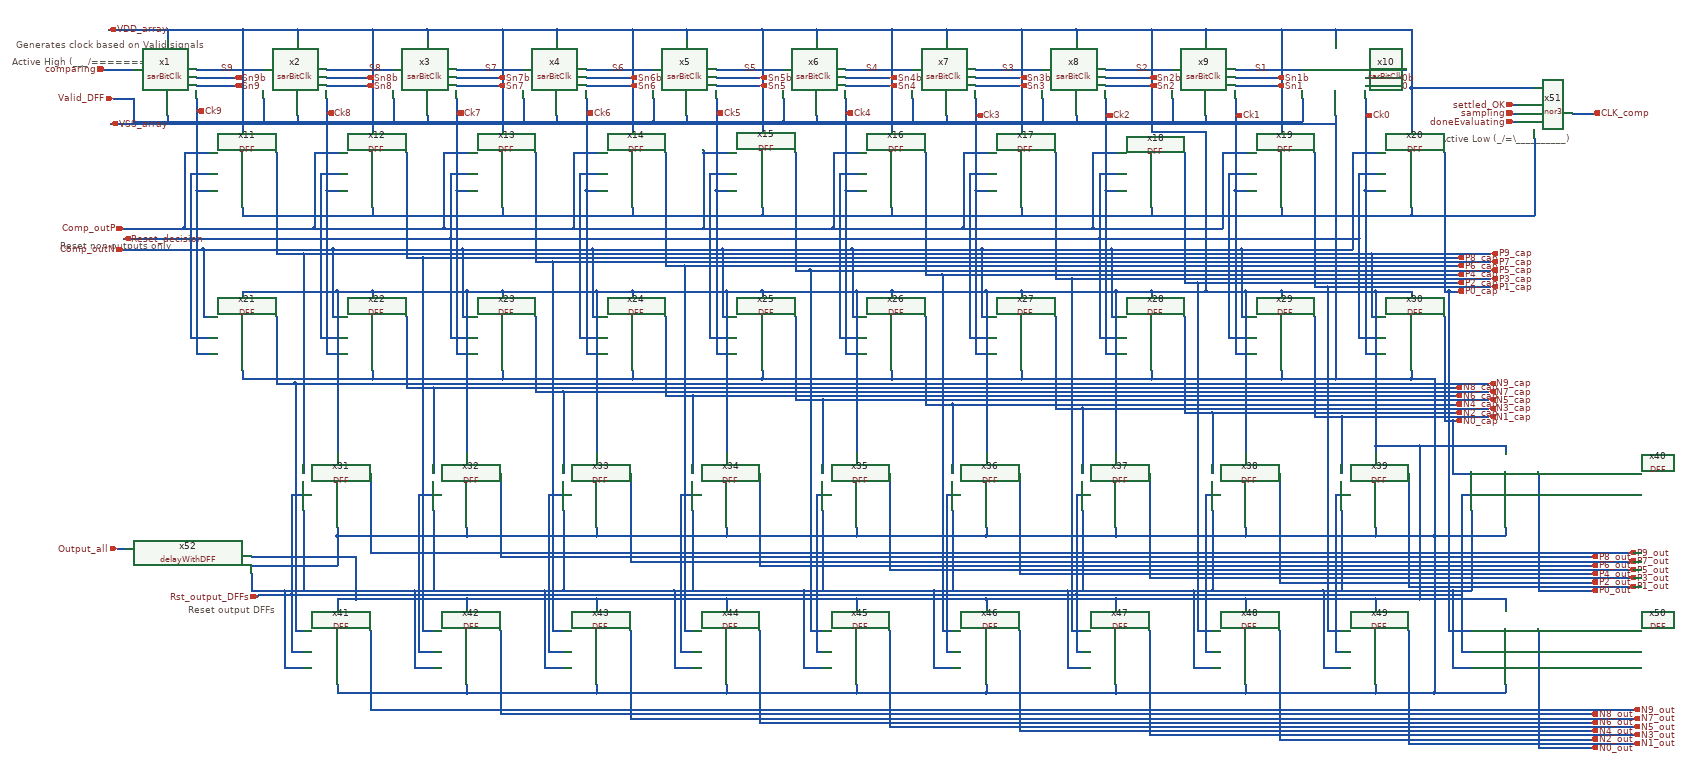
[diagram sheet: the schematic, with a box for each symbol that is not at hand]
v {xschem version=3.4.8RC file_version=1.3}
G {}
K {}
V {}
S {}
F {}
E {}
T {Generates clock based on Valid signals} -520 -755 0 0 0.3 0.3 {}
T {Reset output DFFs} -110 595 0 0 0.3 0.3 {}
T {Active High (___/=========\\_)} -530 -715 0 0 0.3 0.3 {}
T {Active Low (_/=\\__________)} 2880 -530 0 0 0.3 0.3 {}
T {Reset non-outputs only} -415 -275 0 0 0.3 0.3 {}
N -310 -685 -240 -685 {lab=comparing}
N 3195 -580 3245 -580 {lab=CLK_comp}
N 2645 145 2995 145 {lab=N1_cap}
N 2910 155 2915 155 {lab=N0_cap}
N 3115 560 3240 560 {lab=P0_out}
N 2300 -175 2920 -175 {lab=P2_cap}
N 2610 -165 3000 -165 {lab=P1_cap}
N 2900 -155 2920 -155 {lab=P0_cap}
N 2700 -645 2740 -645 {lab=Sn0}
N 2700 -665 2740 -665 {lab=Sn0b}
N -90 -685 70 -685 {lab=S9}
N 220 -685 380 -685 {lab=S8}
N 530 -685 690 -685 {lab=S7}
N 840 -685 1000 -685 {lab=S6}
N 1150 -685 1310 -685 {lab=S5}
N 1460 -685 1620 -685 {lab=S4}
N 1770 -685 1930 -685 {lab=S3}
N 2080 -685 2240 -685 {lab=S2}
N 2390 -685 2550 -685 {lab=S1}
N 2630 -780 2630 -755 {lab=VDD_array}
N 2320 -780 2320 -755 {lab=VDD_array}
N 2190 -780 2320 -780 {lab=VDD_array}
N 2010 -780 2010 -755 {lab=VDD_array}
N 1880 -780 2010 -780 {lab=VDD_array}
N -160 -780 -160 -755 {lab=VDD_array}
N -300 -780 -160 -780 {lab=VDD_array}
N 150 -780 150 -755 {lab=VDD_array}
N 20 -780 150 -780 {lab=VDD_array}
N 460 -780 460 -755 {lab=VDD_array}
N 330 -780 460 -780 {lab=VDD_array}
N 770 -780 770 -755 {lab=VDD_array}
N 640 -780 770 -780 {lab=VDD_array}
N 1390 -780 1390 -755 {lab=VDD_array}
N 1260 -780 1390 -780 {lab=VDD_array}
N 1080 -780 1080 -755 {lab=VDD_array}
N 950 -780 1080 -780 {lab=VDD_array}
N 1700 -780 1700 -755 {lab=VDD_array}
N 1570 -780 1700 -780 {lab=VDD_array}
N -90 -665 0 -665 {lab=Sn9b}
N -90 -645 0 -645 {lab=Sn9}
N 220 -665 315 -665 {lab=Sn8b}
N 220 -645 315 -645 {lab=Sn8}
N 530 -665 630 -665 {lab=Sn7b}
N 530 -645 630 -645 {lab=Sn7}
N 840 -645 945 -645 {lab=Sn6}
N 840 -665 945 -665 {lab=Sn6b}
N 1150 -645 1255 -645 {lab=Sn5}
N 1150 -665 1255 -665 {lab=Sn5b}
N 1460 -665 1565 -665 {lab=Sn4b}
N 1460 -645 1565 -645 {lab=Sn4}
N 1770 -665 1875 -665 {lab=Sn3b}
N 1770 -645 1875 -645 {lab=Sn3}
N 2080 -665 2185 -665 {lab=Sn2b}
N 2080 -645 2185 -645 {lab=Sn2}
N 2630 -575 2630 -555 {lab=VSS_array}
N 2320 -555 2630 -555 {lab=VSS_array}
N 2320 -575 2320 -555 {lab=VSS_array}
N 2010 -555 2320 -555 {lab=VSS_array}
N 2010 -575 2010 -555 {lab=VSS_array}
N -160 -575 -160 -555 {lab=VSS_array}
N 1700 -555 2010 -555 {lab=VSS_array}
N 150 -575 150 -555 {lab=VSS_array}
N -160 -555 150 -555 {lab=VSS_array}
N 460 -575 460 -555 {lab=VSS_array}
N 150 -555 460 -555 {lab=VSS_array}
N 770 -575 770 -555 {lab=VSS_array}
N 460 -555 770 -555 {lab=VSS_array}
N 1390 -575 1390 -555 {lab=VSS_array}
N 1080 -555 1390 -555 {lab=VSS_array}
N 1700 -575 1700 -555 {lab=VSS_array}
N 1390 -555 1700 -555 {lab=VSS_array}
N 1080 -575 1080 -555 {lab=VSS_array}
N 770 -555 1080 -555 {lab=VSS_array}
N 2700 -685 2800 -685 {lab=S0}
N -290 -615 -240 -615 {lab=Valid_DFF}
N -240 -615 -240 -560 {lab=Valid_DFF}
N 2240 -560 2550 -560 {lab=Valid_DFF}
N 2550 -615 2550 -560 {lab=Valid_DFF}
N 2240 -615 2240 -560 {lab=Valid_DFF}
N 1930 -560 2240 -560 {lab=Valid_DFF}
N 1930 -615 1930 -560 {lab=Valid_DFF}
N 1620 -560 1930 -560 {lab=Valid_DFF}
N 1620 -615 1620 -560 {lab=Valid_DFF}
N 1310 -560 1620 -560 {lab=Valid_DFF}
N 1310 -615 1310 -560 {lab=Valid_DFF}
N 1000 -560 1310 -560 {lab=Valid_DFF}
N 1000 -615 1000 -560 {lab=Valid_DFF}
N 690 -560 1000 -560 {lab=Valid_DFF}
N 690 -615 690 -560 {lab=Valid_DFF}
N 380 -560 690 -560 {lab=Valid_DFF}
N 380 -615 380 -560 {lab=Valid_DFF}
N 70 -560 380 -560 {lab=Valid_DFF}
N 70 -615 70 -560 {lab=Valid_DFF}
N -240 -560 70 -560 {lab=Valid_DFF}
N -120 -485 -60 -485 {lab=Comp_outP}
N 20 -780 20 -535 {lab=VDD_array}
N -160 -780 20 -780 {lab=VDD_array}
N -90 -395 -60 -395 {lab=Ck9}
N -90 -615 -90 -395 {lab=Ck9}
N -105 -435 -60 -435 {lab=Reset_decision}
N -120 -485 -120 -305 {lab=Comp_outP}
N -265 -305 -120 -305 {lab=Comp_outP}
N 190 -485 250 -485 {lab=Comp_outP}
N 220 -395 250 -395 {lab=Ck8}
N 220 -615 220 -395 {lab=Ck8}
N 205 -435 250 -435 {lab=Reset_decision}
N 330 -780 330 -535 {lab=VDD_array}
N 150 -780 330 -780 {lab=VDD_array}
N 500 -485 560 -485 {lab=Comp_outP}
N 640 -780 640 -535 {lab=VDD_array}
N 530 -395 560 -395 {lab=Ck7}
N 530 -615 530 -395 {lab=Ck7}
N 515 -435 560 -435 {lab=Reset_decision}
N 810 -485 870 -485 {lab=Comp_outP}
N 840 -395 870 -395 {lab=Ck6}
N 840 -615 840 -395 {lab=Ck6}
N 825 -435 870 -435 {lab=Reset_decision}
N 950 -780 950 -535 {lab=VDD_array}
N 460 -780 640 -780 {lab=VDD_array}
N 770 -780 950 -780 {lab=VDD_array}
N 1120 -485 1180 -485 {lab=Comp_outP}
N 1260 -780 1260 -535 {lab=VDD_array}
N 1150 -395 1180 -395 {lab=Ck5}
N 1150 -615 1150 -395 {lab=Ck5}
N 1135 -435 1180 -435 {lab=Reset_decision}
N 1430 -485 1490 -485 {lab=Comp_outP}
N 1460 -395 1490 -395 {lab=Ck4}
N 1460 -615 1460 -395 {lab=Ck4}
N 1445 -435 1490 -435 {lab=Reset_decision}
N 1570 -780 1570 -535 {lab=VDD_array}
N 1740 -485 1800 -485 {lab=Comp_outP}
N 1880 -780 1880 -535 {lab=VDD_array}
N 1770 -395 1800 -395 {lab=Ck3}
N 1770 -615 1770 -395 {lab=Ck3}
N 1755 -435 1800 -435 {lab=Reset_decision}
N 2050 -485 2110 -485 {lab=Comp_outP}
N 2080 -395 2110 -395 {lab=Ck2}
N 2080 -615 2080 -395 {lab=Ck2}
N 2065 -435 2110 -435 {lab=Reset_decision}
N 2190 -780 2190 -535 {lab=VDD_array}
N 1080 -780 1260 -780 {lab=VDD_array}
N 1390 -780 1570 -780 {lab=VDD_array}
N 1700 -780 1880 -780 {lab=VDD_array}
N 2010 -780 2190 -780 {lab=VDD_array}
N 2360 -485 2420 -485 {lab=Comp_outP}
N 2390 -395 2420 -395 {lab=Ck1}
N 2390 -615 2390 -395 {lab=Ck1}
N 2375 -435 2420 -435 {lab=Reset_decision}
N 2670 -485 2730 -485 {lab=Comp_outN}
N 2700 -395 2730 -395 {lab=Ck0}
N 2700 -615 2700 -395 {lab=Ck0}
N 2685 -435 2730 -435 {lab=Reset_decision}
N 2810 -640 2810 -535 {lab=VDD_array}
N 2500 -780 2630 -780 {lab=VDD_array}
N 2630 -780 2810 -780 {lab=VDD_array}
N 2630 -335 2810 -335 {lab=VSS_array}
N 2810 -355 2810 -335 {lab=VSS_array}
N 2500 -355 2500 -335 {lab=VSS_array}
N 2190 -335 2500 -335 {lab=VSS_array}
N 2190 -355 2190 -335 {lab=VSS_array}
N 1880 -335 2190 -335 {lab=VSS_array}
N 1880 -355 1880 -335 {lab=VSS_array}
N 1570 -335 1880 -335 {lab=VSS_array}
N 1570 -355 1570 -335 {lab=VSS_array}
N 1260 -335 1570 -335 {lab=VSS_array}
N 1260 -355 1260 -335 {lab=VSS_array}
N 950 -335 1260 -335 {lab=VSS_array}
N 950 -355 950 -335 {lab=VSS_array}
N 640 -335 950 -335 {lab=VSS_array}
N 640 -355 640 -335 {lab=VSS_array}
N 330 -335 640 -335 {lab=VSS_array}
N 330 -355 330 -335 {lab=VSS_array}
N 20 -335 330 -335 {lab=VSS_array}
N 20 -355 20 -335 {lab=VSS_array}
N 2630 -555 2630 -335 {lab=VSS_array}
N 2500 -335 2630 -335 {lab=VSS_array}
N 2685 -435 2685 -280 {lab=Reset_decision}
N 2375 -280 2685 -280 {lab=Reset_decision}
N 2375 -435 2375 -280 {lab=Reset_decision}
N 2065 -280 2375 -280 {lab=Reset_decision}
N 2065 -435 2065 -280 {lab=Reset_decision}
N 1755 -280 2065 -280 {lab=Reset_decision}
N 1755 -435 1755 -280 {lab=Reset_decision}
N 1445 -280 1755 -280 {lab=Reset_decision}
N 1445 -435 1445 -280 {lab=Reset_decision}
N 1135 -280 1445 -280 {lab=Reset_decision}
N 1135 -435 1135 -280 {lab=Reset_decision}
N 825 -280 1135 -280 {lab=Reset_decision}
N 825 -435 825 -280 {lab=Reset_decision}
N 515 -280 825 -280 {lab=Reset_decision}
N 515 -435 515 -280 {lab=Reset_decision}
N 205 -280 515 -280 {lab=Reset_decision}
N 205 -435 205 -280 {lab=Reset_decision}
N -105 -280 205 -280 {lab=Reset_decision}
N -105 -435 -105 -280 {lab=Reset_decision}
N -265 -280 -105 -280 {lab=Reset_decision}
N 2405 -255 2670 -255 {lab=Comp_outN}
N 2715 -245 3000 -245 {lab=P9_cap}
N 100 -485 100 -245 {lab=P9_cap}
N 2890 -485 2890 -155 {lab=P0_cap}
N 2580 -485 2580 -165 {lab=P1_cap}
N 2270 -485 2270 -175 {lab=P2_cap}
N 2000 -185 3000 -185 {lab=P3_cap}
N 1960 -485 1960 -185 {lab=P3_cap}
N 1650 -485 1650 -195 {lab=P4_cap}
N 1690 -195 2920 -195 {lab=P4_cap}
N 1340 -485 1340 -205 {lab=P5_cap}
N 1375 -205 3000 -205 {lab=P5_cap}
N 1075 -215 2920 -215 {lab=P6_cap}
N 1030 -485 1030 -215 {lab=P6_cap}
N 720 -485 720 -225 {lab=P7_cap}
N 760 -225 3000 -225 {lab=P7_cap}
N 450 -235 2920 -235 {lab=P8_cap}
N 410 -485 410 -235 {lab=P8_cap}
N -75 -95 -60 -95 {lab=Comp_outN}
N -90 -5 -60 -5 {lab=Ck9}
N -105 -45 -60 -45 {lab=Reset_decision}
N 220 -5 250 -5 {lab=Ck8}
N 205 -45 250 -45 {lab=Reset_decision}
N 530 -5 560 -5 {lab=Ck7}
N 515 -45 560 -45 {lab=Reset_decision}
N 840 -5 870 -5 {lab=Ck6}
N 825 -45 870 -45 {lab=Reset_decision}
N 1150 -5 1180 -5 {lab=Ck5}
N 1135 -45 1180 -45 {lab=Reset_decision}
N 1460 -5 1490 -5 {lab=Ck4}
N 1445 -45 1490 -45 {lab=Reset_decision}
N 1770 -5 1800 -5 {lab=Ck3}
N 1755 -45 1800 -45 {lab=Reset_decision}
N 2080 -5 2110 -5 {lab=Ck2}
N 2065 -45 2110 -45 {lab=Reset_decision}
N 2390 -5 2420 -5 {lab=Ck1}
N 2375 -45 2420 -45 {lab=Reset_decision}
N 2700 -5 2730 -5 {lab=Ck0}
N 2685 -45 2730 -45 {lab=Reset_decision}
N 2810 35 2810 55 {lab=VSS_array}
N 2500 35 2500 55 {lab=VSS_array}
N 2190 55 2500 55 {lab=VSS_array}
N 2190 35 2190 55 {lab=VSS_array}
N 1880 55 2190 55 {lab=VSS_array}
N 1880 35 1880 55 {lab=VSS_array}
N 1570 55 1880 55 {lab=VSS_array}
N 1570 35 1570 55 {lab=VSS_array}
N 1260 55 1570 55 {lab=VSS_array}
N 1260 35 1260 55 {lab=VSS_array}
N 950 55 1260 55 {lab=VSS_array}
N 950 35 950 55 {lab=VSS_array}
N 640 35 640 55 {lab=VSS_array}
N 330 35 330 55 {lab=VSS_array}
N 20 35 20 55 {lab=VSS_array}
N 2630 55 2810 55 {lab=VSS_array}
N -295 -555 -160 -555 {lab=VSS_array}
N 20 -155 20 -145 {lab=VDD_array}
N 2810 -155 2810 -145 {lab=VDD_array}
N 2725 -155 2810 -155 {lab=VDD_array}
N 330 -155 330 -145 {lab=VDD_array}
N 245 -155 330 -155 {lab=VDD_array}
N 640 -155 640 -145 {lab=VDD_array}
N 555 -155 640 -155 {lab=VDD_array}
N 950 -155 950 -145 {lab=VDD_array}
N 865 -155 950 -155 {lab=VDD_array}
N 1260 -155 1260 -145 {lab=VDD_array}
N 1175 -155 1260 -155 {lab=VDD_array}
N 1570 -155 1570 -145 {lab=VDD_array}
N 1485 -155 1570 -155 {lab=VDD_array}
N 2500 -155 2500 -145 {lab=VDD_array}
N 2415 -155 2500 -155 {lab=VDD_array}
N 2190 -155 2190 -145 {lab=VDD_array}
N 2105 -155 2190 -155 {lab=VDD_array}
N 1880 -155 1880 -145 {lab=VDD_array}
N 1795 -155 1880 -155 {lab=VDD_array}
N -75 -255 -75 -95 {lab=Comp_outN}
N -265 -255 -75 -255 {lab=Comp_outN}
N 1165 -95 1180 -95 {lab=Comp_outN}
N -90 -395 -90 -5 {lab=Ck9}
N 220 -395 220 -5 {lab=Ck8}
N 530 -395 530 -5 {lab=Ck7}
N 840 -395 840 -5 {lab=Ck6}
N 1150 -395 1150 -5 {lab=Ck5}
N 2700 -395 2700 -5 {lab=Ck0}
N 2390 -395 2390 -5 {lab=Ck1}
N 2080 -395 2080 -5 {lab=Ck2}
N 1770 -395 1770 -5 {lab=Ck3}
N 1460 -395 1460 -5 {lab=Ck4}
N 235 -95 250 -95 {lab=Comp_outN}
N 545 -95 560 -95 {lab=Comp_outN}
N 855 -95 870 -95 {lab=Comp_outN}
N 2405 -95 2420 -95 {lab=Comp_outN}
N 2715 -95 2730 -95 {lab=P9_cap}
N 1785 -95 1800 -95 {lab=Comp_outN}
N 2095 -95 2110 -95 {lab=Comp_outN}
N 1475 -95 1490 -95 {lab=Comp_outN}
N -105 -280 -105 -45 {lab=Reset_decision}
N 205 -280 205 -45 {lab=Reset_decision}
N 515 -280 515 -45 {lab=Reset_decision}
N 825 -280 825 -45 {lab=Reset_decision}
N 1135 -280 1135 -45 {lab=Reset_decision}
N 1445 -280 1445 -45 {lab=Reset_decision}
N 1755 -280 1755 -45 {lab=Reset_decision}
N 2065 -280 2065 -45 {lab=Reset_decision}
N 2375 -280 2375 -45 {lab=Reset_decision}
N 2685 -280 2685 -45 {lab=Reset_decision}
N 2890 -95 2890 155 {lab=N0_cap}
N 2580 -95 2580 145 {lab=N1_cap}
N 2335 135 2915 135 {lab=N2_cap}
N 2270 -95 2270 135 {lab=N2_cap}
N 1650 -95 1650 115 {lab=N4_cap}
N 1715 115 2915 115 {lab=N4_cap}
N 1960 -95 1960 125 {lab=N3_cap}
N 2025 125 2995 125 {lab=N3_cap}
N 145 65 2995 65 {lab=N9_cap}
N 100 -95 100 65 {lab=N9_cap}
N 475 75 2915 75 {lab=N8_cap}
N 410 -95 410 75 {lab=N8_cap}
N 720 -95 720 85 {lab=N7_cap}
N 785 85 2995 85 {lab=N7_cap}
N 1030 -95 1030 95 {lab=N6_cap}
N 1095 95 2915 95 {lab=N6_cap}
N 1340 -95 1340 105 {lab=N5_cap}
N 1405 105 2995 105 {lab=N5_cap}
N 640 55 950 55 {lab=VSS_array}
N 20 55 330 55 {lab=VSS_array}
N 2190 -535 2320 -535 {lab=VDD_array}
N 2320 -535 2320 -155 {lab=VDD_array}
N 2190 -155 2320 -155 {lab=VDD_array}
N 2390 -645 2490 -645 {lab=Sn1}
N 2390 -665 2490 -665 {lab=Sn1b}
N 2500 -780 2500 -535 {lab=VDD_array}
N 2320 -780 2500 -780 {lab=VDD_array}
N 2630 -335 2630 55 {lab=VSS_array}
N 2500 55 2630 55 {lab=VSS_array}
N 20 -155 245 -155 {lab=VDD_array}
N 330 -155 555 -155 {lab=VDD_array}
N 865 -155 865 230 {lab=VDD_array}
N 640 -155 865 -155 {lab=VDD_array}
N 245 -155 245 230 {lab=VDD_array}
N 555 -155 555 230 {lab=VDD_array}
N 1175 -155 1175 230 {lab=VDD_array}
N 950 -155 1175 -155 {lab=VDD_array}
N 1485 -155 1485 230 {lab=VDD_array}
N 1260 -155 1485 -155 {lab=VDD_array}
N 1795 -155 1795 230 {lab=VDD_array}
N 1570 -155 1795 -155 {lab=VDD_array}
N 2105 -155 2105 230 {lab=VDD_array}
N 1880 -155 2105 -155 {lab=VDD_array}
N 2415 -155 2415 230 {lab=VDD_array}
N 2320 -155 2415 -155 {lab=VDD_array}
N 2725 215 2725 230 {lab=VDD_array}
N 2500 -155 2725 -155 {lab=VDD_array}
N 3035 215 3035 230 {lab=VDD_array}
N 2830 215 3035 215 {lab=VDD_array}
N 2725 -155 2725 215 {lab=VDD_array}
N 165 -245 165 280 {lab=P9_cap}
N 100 -245 165 -245 {lab=P9_cap}
N 410 75 475 75 {lab=N8_cap}
N 475 75 475 280 {lab=N8_cap}
N 785 85 785 280 {lab=N7_cap}
N 720 85 785 85 {lab=N7_cap}
N 1095 95 1095 280 {lab=N6_cap}
N 1030 95 1095 95 {lab=N6_cap}
N 1405 105 1405 280 {lab=N5_cap}
N 1340 105 1405 105 {lab=N5_cap}
N 1715 115 1715 280 {lab=N4_cap}
N 1650 115 1715 115 {lab=N4_cap}
N 2025 125 2025 280 {lab=N3_cap}
N 1960 125 2025 125 {lab=N3_cap}
N 2335 135 2335 280 {lab=N2_cap}
N 2270 135 2335 135 {lab=N2_cap}
N 2645 145 2645 280 {lab=N1_cap}
N 2580 145 2645 145 {lab=N1_cap}
N 2910 155 2910 280 {lab=N0_cap}
N 2890 155 2910 155 {lab=N0_cap}
N 2910 280 2955 280 {lab=N0_cap}
N 3115 280 3115 560 {lab=P0_out}
N 2805 280 2805 550 {lab=P1_out}
N 2805 550 3340 550 {lab=P1_out}
N 2495 280 2495 540 {lab=P2_out}
N 2495 540 3240 540 {lab=P2_out}
N 2185 530 3340 530 {lab=P3_out}
N 2185 280 2185 530 {lab=P3_out}
N 1875 520 3240 520 {lab=P4_out}
N 1565 280 1565 510 {lab=P5_out}
N 1565 510 3340 510 {lab=P5_out}
N 1875 280 1875 520 {lab=P4_out}
N 1255 280 1255 500 {lab=P6_out}
N 1255 500 3240 500 {lab=P6_out}
N 945 490 3340 490 {lab=P7_out}
N 945 280 945 490 {lab=P7_out}
N 635 480 3240 480 {lab=P8_out}
N 325 470 3340 470 {lab=P9_out}
N 325 280 325 470 {lab=P9_out}
N 635 280 635 480 {lab=P8_out}
N 3035 410 3035 430 {lab=VSS_array}
N 2865 430 3035 430 {lab=VSS_array}
N 2725 410 2725 430 {lab=VSS_array}
N 2415 430 2725 430 {lab=VSS_array}
N 2415 410 2415 430 {lab=VSS_array}
N 2105 430 2415 430 {lab=VSS_array}
N 2810 55 2865 55 {lab=VSS_array}
N 2865 55 2865 430 {lab=VSS_array}
N 2725 430 2865 430 {lab=VSS_array}
N 2105 410 2105 430 {lab=VSS_array}
N 1795 430 2105 430 {lab=VSS_array}
N 1795 410 1795 430 {lab=VSS_array}
N 1485 430 1795 430 {lab=VSS_array}
N 1485 410 1485 430 {lab=VSS_array}
N 1175 430 1485 430 {lab=VSS_array}
N 245 410 245 430 {lab=VSS_array}
N 555 410 555 430 {lab=VSS_array}
N 865 410 865 430 {lab=VSS_array}
N 555 430 865 430 {lab=VSS_array}
N 1175 410 1175 430 {lab=VSS_array}
N 865 430 1175 430 {lab=VSS_array}
N 3115 655 3115 935 {lab=N0_out}
N 2805 655 2805 925 {lab=N1_out}
N 2495 655 2495 915 {lab=N2_out}
N 2185 655 2185 905 {lab=N3_out}
N 1565 655 1565 885 {lab=N5_out}
N 1875 655 1875 895 {lab=N4_out}
N 1255 655 1255 875 {lab=N6_out}
N 945 655 945 865 {lab=N7_out}
N 635 855 3240 855 {lab=N8_out}
N 325 655 325 845 {lab=N9_out}
N 635 655 635 855 {lab=N8_out}
N 3035 785 3035 805 {lab=VSS_array}
N 2865 805 3035 805 {lab=VSS_array}
N 2725 785 2725 805 {lab=VSS_array}
N 2415 805 2725 805 {lab=VSS_array}
N 2415 785 2415 805 {lab=VSS_array}
N 2105 805 2415 805 {lab=VSS_array}
N 2865 430 2865 805 {lab=VSS_array}
N 2725 805 2865 805 {lab=VSS_array}
N 2105 785 2105 805 {lab=VSS_array}
N 1795 805 2105 805 {lab=VSS_array}
N 1795 785 1795 805 {lab=VSS_array}
N 1485 805 1795 805 {lab=VSS_array}
N 1485 785 1485 805 {lab=VSS_array}
N 1175 805 1485 805 {lab=VSS_array}
N 245 785 245 805 {lab=VSS_array}
N 555 785 555 805 {lab=VSS_array}
N 865 785 865 805 {lab=VSS_array}
N 555 805 865 805 {lab=VSS_array}
N 1175 785 1175 805 {lab=VSS_array}
N 865 805 1175 805 {lab=VSS_array}
N 325 845 3340 845 {lab=N9_out}
N 145 65 145 655 {lab=N9_cap}
N 100 65 145 65 {lab=N9_cap}
N 145 655 165 655 {lab=N9_cap}
N 450 -235 450 655 {lab=P8_cap}
N 410 -235 450 -235 {lab=P8_cap}
N 450 655 475 655 {lab=P8_cap}
N 760 -225 760 655 {lab=P7_cap}
N 720 -225 760 -225 {lab=P7_cap}
N 760 655 785 655 {lab=P7_cap}
N 1075 655 1095 655 {lab=P6_cap}
N 1075 -215 1075 655 {lab=P6_cap}
N 1030 -215 1075 -215 {lab=P6_cap}
N 1375 655 1405 655 {lab=P5_cap}
N 1375 -205 1375 655 {lab=P5_cap}
N 1340 -205 1375 -205 {lab=P5_cap}
N 1690 655 1715 655 {lab=P4_cap}
N 1690 -195 1690 655 {lab=P4_cap}
N 1650 -195 1690 -195 {lab=P4_cap}
N 2000 655 2025 655 {lab=P3_cap}
N 2000 -185 2000 655 {lab=P3_cap}
N 1960 -185 2000 -185 {lab=P3_cap}
N 2300 655 2335 655 {lab=P2_cap}
N 2300 -175 2300 655 {lab=P2_cap}
N 2270 -175 2300 -175 {lab=P2_cap}
N 2610 655 2645 655 {lab=P1_cap}
N 2610 -165 2610 655 {lab=P1_cap}
N 2580 -165 2610 -165 {lab=P1_cap}
N 2900 -155 2900 655 {lab=P0_cap}
N 2890 -155 2900 -155 {lab=P0_cap}
N 2900 655 2955 655 {lab=P0_cap}
N 3115 935 3240 935 {lab=N0_out}
N 2805 925 3340 925 {lab=N1_out}
N 2495 915 3240 915 {lab=N2_out}
N 2185 905 3340 905 {lab=N3_out}
N 1875 895 3240 895 {lab=N4_out}
N 1565 885 3340 885 {lab=N5_out}
N 945 865 3340 865 {lab=N7_out}
N 1255 875 3240 875 {lab=N6_out}
N 3035 580 3035 605 {lab=VDD_array}
N 2830 580 3035 580 {lab=VDD_array}
N 245 580 245 605 {lab=VDD_array}
N 555 580 555 605 {lab=VDD_array}
N 290 580 555 580 {lab=VDD_array}
N 865 580 865 605 {lab=VDD_array}
N 555 580 865 580 {lab=VDD_array}
N 2725 580 2725 605 {lab=VDD_array}
N 2415 580 2725 580 {lab=VDD_array}
N 2415 580 2415 605 {lab=VDD_array}
N 2105 580 2415 580 {lab=VDD_array}
N 2105 580 2105 605 {lab=VDD_array}
N 1795 580 2105 580 {lab=VDD_array}
N 1795 580 1795 605 {lab=VDD_array}
N 1485 580 1795 580 {lab=VDD_array}
N 1485 580 1485 605 {lab=VDD_array}
N 1175 580 1485 580 {lab=VDD_array}
N 1175 580 1175 605 {lab=VDD_array}
N 865 580 1175 580 {lab=VDD_array}
N 2725 215 2830 215 {lab=VDD_array}
N 2725 580 2830 580 {lab=VDD_array}
N 2830 215 2830 580 {lab=VDD_array}
N 245 805 555 805 {lab=VSS_array}
N 330 55 640 55 {lab=VSS_array}
N 245 430 555 430 {lab=VSS_array}
N 2955 370 2955 560 {lab=#net1}
N 2910 560 2955 560 {lab=#net1}
N 2645 370 2645 560 {lab=#net1}
N 2600 560 2645 560 {lab=#net1}
N 2335 370 2335 560 {lab=#net1}
N 2290 560 2335 560 {lab=#net1}
N 165 370 165 560 {lab=#net1}
N 120 560 165 560 {lab=#net1}
N 475 370 475 560 {lab=#net1}
N 430 560 475 560 {lab=#net1}
N 785 370 785 560 {lab=#net1}
N 740 560 785 560 {lab=#net1}
N 1095 370 1095 560 {lab=#net1}
N 1050 560 1095 560 {lab=#net1}
N 1405 370 1405 560 {lab=#net1}
N 1360 560 1405 560 {lab=#net1}
N 1715 370 1715 560 {lab=#net1}
N 1670 560 1715 560 {lab=#net1}
N 2025 370 2025 560 {lab=#net1}
N 1990 560 2025 560 {lab=#net1}
N 1990 560 1990 745 {lab=#net1}
N 1715 560 1990 560 {lab=#net1}
N 1990 745 2025 745 {lab=#net1}
N 2290 560 2290 745 {lab=#net1}
N 2290 745 2335 745 {lab=#net1}
N 2025 560 2290 560 {lab=#net1}
N 1670 560 1670 745 {lab=#net1}
N 1670 745 1715 745 {lab=#net1}
N 1405 560 1670 560 {lab=#net1}
N 1360 560 1360 745 {lab=#net1}
N 1360 745 1405 745 {lab=#net1}
N 1095 560 1360 560 {lab=#net1}
N 1050 560 1050 745 {lab=#net1}
N 1050 745 1095 745 {lab=#net1}
N 785 560 1050 560 {lab=#net1}
N 120 560 120 745 {lab=#net1}
N 120 745 165 745 {lab=#net1}
N 430 560 430 745 {lab=#net1}
N 430 745 475 745 {lab=#net1}
N 165 560 430 560 {lab=#net1}
N 740 560 740 745 {lab=#net1}
N 740 745 785 745 {lab=#net1}
N 475 560 740 560 {lab=#net1}
N 2910 560 2910 745 {lab=#net1}
N 2910 745 2955 745 {lab=#net1}
N 2645 560 2910 560 {lab=#net1}
N 2600 560 2600 745 {lab=#net1}
N 2600 745 2645 745 {lab=#net1}
N 2335 560 2600 560 {lab=#net1}
N 2930 330 2955 330 {lab=Rst_output_DFFs}
N 2930 330 2930 570 {lab=Rst_output_DFFs}
N 2630 570 2930 570 {lab=Rst_output_DFFs}
N 2930 570 2930 705 {lab=Rst_output_DFFs}
N 2930 705 2955 705 {lab=Rst_output_DFFs}
N 2630 705 2645 705 {lab=Rst_output_DFFs}
N 2630 570 2630 705 {lab=Rst_output_DFFs}
N 2320 570 2630 570 {lab=Rst_output_DFFs}
N 2630 330 2630 570 {lab=Rst_output_DFFs}
N 2630 330 2645 330 {lab=Rst_output_DFFs}
N 2320 330 2335 330 {lab=Rst_output_DFFs}
N 2320 330 2320 570 {lab=Rst_output_DFFs}
N 2010 570 2320 570 {lab=Rst_output_DFFs}
N 2320 570 2320 705 {lab=Rst_output_DFFs}
N 2320 705 2335 705 {lab=Rst_output_DFFs}
N 2010 330 2025 330 {lab=Rst_output_DFFs}
N 2010 330 2010 570 {lab=Rst_output_DFFs}
N 1700 570 2010 570 {lab=Rst_output_DFFs}
N 2010 570 2010 705 {lab=Rst_output_DFFs}
N 2010 705 2025 705 {lab=Rst_output_DFFs}
N 1700 330 1700 570 {lab=Rst_output_DFFs}
N 1390 570 1700 570 {lab=Rst_output_DFFs}
N 1700 330 1715 330 {lab=Rst_output_DFFs}
N 1700 570 1700 705 {lab=Rst_output_DFFs}
N 1700 705 1715 705 {lab=Rst_output_DFFs}
N 1390 330 1405 330 {lab=Rst_output_DFFs}
N 1390 330 1390 570 {lab=Rst_output_DFFs}
N 1065 570 1390 570 {lab=Rst_output_DFFs}
N 1390 570 1390 705 {lab=Rst_output_DFFs}
N 1390 705 1405 705 {lab=Rst_output_DFFs}
N 1065 330 1095 330 {lab=Rst_output_DFFs}
N 1065 330 1065 570 {lab=Rst_output_DFFs}
N 750 570 1065 570 {lab=Rst_output_DFFs}
N 1065 570 1065 705 {lab=Rst_output_DFFs}
N 1065 705 1095 705 {lab=Rst_output_DFFs}
N 135 330 165 330 {lab=Rst_output_DFFs}
N 135 330 135 570 {lab=Rst_output_DFFs}
N 60 570 135 570 {lab=Rst_output_DFFs}
N 135 570 135 705 {lab=Rst_output_DFFs}
N 135 705 165 705 {lab=Rst_output_DFFs}
N 440 705 475 705 {lab=Rst_output_DFFs}
N 440 570 440 705 {lab=Rst_output_DFFs}
N 135 570 440 570 {lab=Rst_output_DFFs}
N 440 330 440 570 {lab=Rst_output_DFFs}
N 440 330 475 330 {lab=Rst_output_DFFs}
N 750 705 785 705 {lab=Rst_output_DFFs}
N 750 570 750 705 {lab=Rst_output_DFFs}
N 440 570 750 570 {lab=Rst_output_DFFs}
N 750 330 750 570 {lab=Rst_output_DFFs}
N 750 330 785 330 {lab=Rst_output_DFFs}
N 3055 -560 3065 -560 {lab=doneEvaluating}
N 2810 -640 3105 -640 {lab=VDD_array}
N 2810 -780 2810 -640 {lab=VDD_array}
N 2810 -335 3105 -335 {lab=VSS_array}
N 3105 -520 3105 -335 {lab=VSS_array}
N 3055 -580 3065 -580 {lab=sampling}
N 55 575 60 570 {lab=Rst_output_DFFs}
N 3055 -600 3065 -600 {lab=settled_OK}
N 190 -485 190 -305 {lab=Comp_outP}
N -120 -305 190 -305 {lab=Comp_outP}
N 235 -255 235 -95 {lab=Comp_outN}
N -75 -255 235 -255 {lab=Comp_outN}
N 545 -255 545 -95 {lab=Comp_outN}
N 235 -255 545 -255 {lab=Comp_outN}
N 500 -485 500 -305 {lab=Comp_outP}
N 190 -305 500 -305 {lab=Comp_outP}
N 855 -255 855 -95 {lab=Comp_outN}
N 545 -255 855 -255 {lab=Comp_outN}
N 810 -485 810 -305 {lab=Comp_outP}
N 500 -305 810 -305 {lab=Comp_outP}
N 1120 -485 1120 -305 {lab=Comp_outP}
N 1120 -490 1120 -485 {lab=Comp_outP}
N 810 -305 1120 -305 {lab=Comp_outP}
N 1165 -255 1165 -95 {lab=Comp_outN}
N 855 -255 1165 -255 {lab=Comp_outN}
N 1475 -255 1475 -95 {lab=Comp_outN}
N 1165 -255 1475 -255 {lab=Comp_outN}
N 1430 -485 1430 -305 {lab=Comp_outP}
N 1120 -305 1430 -305 {lab=Comp_outP}
N 1740 -485 1740 -305 {lab=Comp_outP}
N 1430 -305 1740 -305 {lab=Comp_outP}
N 1785 -255 1785 -95 {lab=Comp_outN}
N 1475 -255 1785 -255 {lab=Comp_outN}
N 2095 -255 2095 -95 {lab=Comp_outN}
N 1785 -255 2095 -255 {lab=Comp_outN}
N 2050 -485 2050 -305 {lab=Comp_outP}
N 1740 -305 2050 -305 {lab=Comp_outP}
N 2360 -485 2360 -305 {lab=Comp_outP}
N 2050 -305 2360 -305 {lab=Comp_outP}
N 2405 -255 2405 -95 {lab=Comp_outN}
N 2095 -255 2405 -255 {lab=Comp_outN}
N 2715 -245 2715 -95 {lab=P9_cap}
N 165 -245 2715 -245 {lab=P9_cap}
N 2670 -485 2670 -255 {lab=Comp_outN}
N -280 460 -260 460 {lab=Output_all}
N 40 520 40 560 {lab=#net1}
N 40 560 120 560 {lab=#net1}
N 40 500 245 500 {lab=VSS_array}
N 245 430 245 500 {lab=VSS_array}
N 40 480 290 480 {lab=VDD_array}
N 290 480 290 580 {lab=VDD_array}
N 245 580 290 580 {lab=VDD_array}
C {opin.sym} 2920 -155 0 0 {name=p21 lab=P0_cap}
C {opin.sym} 3000 -245 0 0 {name=p22 lab=P9_cap}
C {opin.sym} 2920 -235 0 0 {name=p23 lab=P8_cap}
C {opin.sym} 3000 -225 0 0 {name=p24 lab=P7_cap}
C {opin.sym} 2920 -215 0 0 {name=p25 lab=P6_cap}
C {opin.sym} 3000 -205 0 0 {name=p26 lab=P5_cap}
C {opin.sym} 3000 -185 0 0 {name=p27 lab=P3_cap}
C {opin.sym} 3000 -165 0 0 {name=p28 lab=P1_cap}
C {opin.sym} 2920 -195 0 0 {name=p29 lab=P4_cap}
C {opin.sym} 2995 65 0 0 {name=p30 lab=N9_cap}
C {opin.sym} 2915 155 0 0 {name=p31 lab=N0_cap}
C {opin.sym} 2920 -175 0 0 {name=p32 lab=P2_cap}
C {opin.sym} 2995 85 0 0 {name=p33 lab=N7_cap}
C {opin.sym} 2915 75 0 0 {name=p34 lab=N8_cap}
C {opin.sym} 2995 105 0 0 {name=p35 lab=N5_cap}
C {opin.sym} 2915 95 0 0 {name=p36 lab=N6_cap}
C {opin.sym} 2995 125 0 0 {name=p37 lab=N3_cap}
C {opin.sym} 2915 115 0 0 {name=p38 lab=N4_cap}
C {opin.sym} 2995 145 0 0 {name=p39 lab=N1_cap}
C {opin.sym} 2915 135 0 0 {name=p40 lab=N2_cap}
C {opin.sym} 3330 470 0 0 {name=p41 lab=P9_out}
C {opin.sym} 3240 480 0 0 {name=p42 lab=P8_out}
C {opin.sym} 3330 490 0 0 {name=p43 lab=P7_out}
C {opin.sym} 3240 500 0 0 {name=p44 lab=P6_out}
C {opin.sym} 3330 510 0 0 {name=p45 lab=P5_out}
C {opin.sym} 3240 520 0 0 {name=p46 lab=P4_out}
C {opin.sym} 3240 540 0 0 {name=p47 lab=P2_out}
C {opin.sym} 3240 560 0 0 {name=p48 lab=P0_out}
C {opin.sym} 3330 550 0 0 {name=p49 lab=P1_out}
C {opin.sym} 3330 530 0 0 {name=p50 lab=P3_out}
C {opin.sym} 3340 845 0 0 {name=p1 lab=N9_out}
C {opin.sym} 3340 865 0 0 {name=p2 lab=N7_out}
C {opin.sym} 3340 885 0 0 {name=p3 lab=N5_out}
C {opin.sym} 3340 905 0 0 {name=p4 lab=N3_out}
C {opin.sym} 3340 925 0 0 {name=p5 lab=N1_out}
C {opin.sym} 3240 855 0 0 {name=p6 lab=N8_out}
C {opin.sym} 3240 875 0 0 {name=p7 lab=N6_out}
C {opin.sym} 3240 895 0 0 {name=p8 lab=N4_out}
C {opin.sym} 3240 915 0 0 {name=p9 lab=N2_out}
C {opin.sym} 3240 935 0 0 {name=p10 lab=N0_out}
C {iopin.sym} -300 -780 0 1 {name=p11 lab=VDD_array}
C {ipin.sym} -310 -685 0 0 {name=p13 lab=comparing}
C {ipin.sym} -290 -615 0 0 {name=p14 lab=Valid_DFF}
C {iopin.sym} -295 -555 0 1 {name=p15 lab=VSS_array}
C {ipin.sym} -265 -305 0 0 {name=p16 lab=Comp_outP}
C {ipin.sym} -265 -255 0 0 {name=p17 lab=Comp_outN}
C {ipin.sym} -280 460 0 0 {name=p18 lab=Output_all}
C {ipin.sym} 55 575 0 0 {name=p19 lab=Rst_output_DFFs}
C {opin.sym} 3245 -580 0 0 {name=p20 lab=CLK_comp}
C {ipin.sym} 3055 -580 0 0 {name=p12 lab=sampling}
C {opin.sym} -90 -585 0 0 {name=p52 lab=Ck9}
C {opin.sym} 220 -580 0 0 {name=p53 lab=Ck8}
C {opin.sym} 530 -580 0 0 {name=p54 lab=Ck7}
C {opin.sym} 840 -580 0 0 {name=p55 lab=Ck6}
C {opin.sym} 1150 -580 0 0 {name=p56 lab=Ck5}
C {opin.sym} 1460 -580 0 0 {name=p57 lab=Ck4}
C {opin.sym} 1770 -575 0 0 {name=p58 lab=Ck3}
C {opin.sym} 2080 -575 0 0 {name=p59 lab=Ck2}
C {opin.sym} 2390 -575 0 0 {name=p60 lab=Ck1}
C {opin.sym} 2700 -575 0 0 {name=p61 lab=Ck0}
C {lab_wire.sym} 0 -685 0 0 {name=p62 sig_type=std_logic lab=S9}
C {lab_wire.sym} 355 -685 0 0 {name=p63 sig_type=std_logic lab=S8}
C {lab_wire.sym} 630 -685 0 0 {name=p64 sig_type=std_logic lab=S7}
C {lab_wire.sym} 935 -685 0 0 {name=p65 sig_type=std_logic lab=S6}
C {lab_wire.sym} 1250 -685 0 0 {name=p66 sig_type=std_logic lab=S5}
C {lab_wire.sym} 1540 -685 0 0 {name=p67 sig_type=std_logic lab=S4}
C {lab_wire.sym} 1865 -685 0 0 {name=p68 sig_type=std_logic lab=S3}
C {lab_wire.sym} 2185 -685 0 0 {name=p69 sig_type=std_logic lab=S2}
C {lab_wire.sym} 2470 -685 0 0 {name=p70 sig_type=std_logic lab=S1}
C {lab_wire.sym} 2775 -685 0 0 {name=p71 sig_type=std_logic lab=S0}
C {opin.sym} 2740 -645 0 0 {name=p82 lab=Sn0}
C {opin.sym} 2740 -665 0 0 {name=p77 lab=Sn0b}
C {opin.sym} 2490 -645 0 0 {name=p72 lab=Sn1}
C {opin.sym} 2490 -665 0 0 {name=p73 lab=Sn1b}
C {opin.sym} 2185 -645 0 0 {name=p74 lab=Sn2}
C {opin.sym} 2185 -665 0 0 {name=p75 lab=Sn2b}
C {opin.sym} 1875 -645 0 0 {name=p76 lab=Sn3}
C {opin.sym} 1875 -665 0 0 {name=p78 lab=Sn3b}
C {opin.sym} 0 -645 0 0 {name=p79 lab=Sn9}
C {opin.sym} 0 -665 0 0 {name=p80 lab=Sn9b}
C {opin.sym} 315 -645 0 0 {name=p81 lab=Sn8}
C {opin.sym} 315 -665 0 0 {name=p83 lab=Sn8b}
C {opin.sym} 630 -645 0 0 {name=p84 lab=Sn7}
C {opin.sym} 630 -665 0 0 {name=p85 lab=Sn7b}
C {opin.sym} 945 -645 0 0 {name=p86 lab=Sn6}
C {opin.sym} 945 -665 0 0 {name=p87 lab=Sn6b}
C {opin.sym} 1255 -645 0 0 {name=p88 lab=Sn5}
C {opin.sym} 1255 -665 0 0 {name=p89 lab=Sn5b}
C {opin.sym} 1565 -645 0 0 {name=p90 lab=Sn4}
C {opin.sym} 1565 -665 0 0 {name=p91 lab=Sn4b}
C {ipin.sym} 3055 -600 0 0 {name=p92 lab=settled_OK}
C {ipin.sym} 3055 -560 0 0 {name=p93 lab=doneEvaluating}
C {iopin.sym} -265 -280 0 1 {name=p94 lab=Reset_decision}
C {/foss/designs/sarADC/sarBitClk.sym} -160 -655 0 0 {name=x1}
C {/foss/designs/sarADC/sarBitClk.sym} 150 -655 0 0 {name=x2}
C {/foss/designs/sarADC/sarBitClk.sym} 460 -655 0 0 {name=x3}
C {/foss/designs/sarADC/sarBitClk.sym} 770 -655 0 0 {name=x4}
C {/foss/designs/sarADC/sarBitClk.sym} 1080 -655 0 0 {name=x5}
C {/foss/designs/sarADC/sarBitClk.sym} 1390 -655 0 0 {name=x6}
C {/foss/designs/sarADC/sarBitClk.sym} 1700 -655 0 0 {name=x7}
C {/foss/designs/sarADC/sarBitClk.sym} 2010 -655 0 0 {name=x8}
C {/foss/designs/sarADC/sarBitClk.sym} 2320 -655 0 0 {name=x9}
C {/foss/designs/sarADC/sarBitClk.sym} 2630 -655 0 0 {name=x10}
C {/foss/designs/sarADC/DFF.sym} 20 -445 0 0 {name=x11}
C {/foss/designs/sarADC/DFF.sym} 330 -445 0 0 {name=x12}
C {/foss/designs/sarADC/DFF.sym} 640 -445 0 0 {name=x13}
C {/foss/designs/sarADC/DFF.sym} 950 -445 0 0 {name=x14}
C {/foss/designs/sarADC/DFF.sym} 1260 -445 0 0 {name=x15}
C {/foss/designs/sarADC/DFF.sym} 1570 -445 0 0 {name=x16}
C {/foss/designs/sarADC/DFF.sym} 1880 -445 0 0 {name=x17}
C {/foss/designs/sarADC/DFF.sym} 2190 -445 0 0 {name=x18}
C {/foss/designs/sarADC/DFF.sym} 2500 -445 0 0 {name=x19}
C {/foss/designs/sarADC/DFF.sym} 2810 -445 0 0 {name=x20}
C {/foss/designs/sarADC/DFF.sym} 20 -55 0 0 {name=x21}
C {/foss/designs/sarADC/DFF.sym} 330 -55 0 0 {name=x22}
C {/foss/designs/sarADC/DFF.sym} 640 -55 0 0 {name=x23}
C {/foss/designs/sarADC/DFF.sym} 950 -55 0 0 {name=x24}
C {/foss/designs/sarADC/DFF.sym} 1260 -55 0 0 {name=x25}
C {/foss/designs/sarADC/DFF.sym} 1570 -55 0 0 {name=x26}
C {/foss/designs/sarADC/DFF.sym} 1880 -55 0 0 {name=x27}
C {/foss/designs/sarADC/DFF.sym} 2190 -55 0 0 {name=x28}
C {/foss/designs/sarADC/DFF.sym} 2500 -55 0 0 {name=x29}
C {/foss/designs/sarADC/DFF.sym} 2810 -55 0 0 {name=x30}
C {/foss/designs/sarADC/DFF.sym} 245 320 0 0 {name=x31}
C {/foss/designs/sarADC/DFF.sym} 555 320 0 0 {name=x32}
C {/foss/designs/sarADC/DFF.sym} 865 320 0 0 {name=x33}
C {/foss/designs/sarADC/DFF.sym} 1175 320 0 0 {name=x34}
C {/foss/designs/sarADC/DFF.sym} 1485 320 0 0 {name=x35}
C {/foss/designs/sarADC/DFF.sym} 1795 320 0 0 {name=x36}
C {/foss/designs/sarADC/DFF.sym} 2105 320 0 0 {name=x37}
C {/foss/designs/sarADC/DFF.sym} 2415 320 0 0 {name=x38}
C {/foss/designs/sarADC/DFF.sym} 2725 320 0 0 {name=x39}
C {/foss/designs/sarADC/DFF.sym} 3035 320 0 0 {name=x40}
C {/foss/designs/sarADC/DFF.sym} 245 695 0 0 {name=x41}
C {/foss/designs/sarADC/DFF.sym} 555 695 0 0 {name=x42}
C {/foss/designs/sarADC/DFF.sym} 865 695 0 0 {name=x43}
C {/foss/designs/sarADC/DFF.sym} 1175 695 0 0 {name=x44}
C {/foss/designs/sarADC/DFF.sym} 1485 695 0 0 {name=x45}
C {/foss/designs/sarADC/DFF.sym} 1795 695 0 0 {name=x46}
C {/foss/designs/sarADC/DFF.sym} 2105 695 0 0 {name=x47}
C {/foss/designs/sarADC/DFF.sym} 2415 695 0 0 {name=x48}
C {/foss/designs/sarADC/DFF.sym} 2725 695 0 0 {name=x49}
C {/foss/designs/sarADC/DFF.sym} 3035 695 0 0 {name=x50}
C {/foss/designs/sarADC/nor3.sym} 3105 -580 0 0 {name=x51}
C {/foss/designs/sarADC/delayWithDFF.sym} -110 480 0 0 {name=x52}
